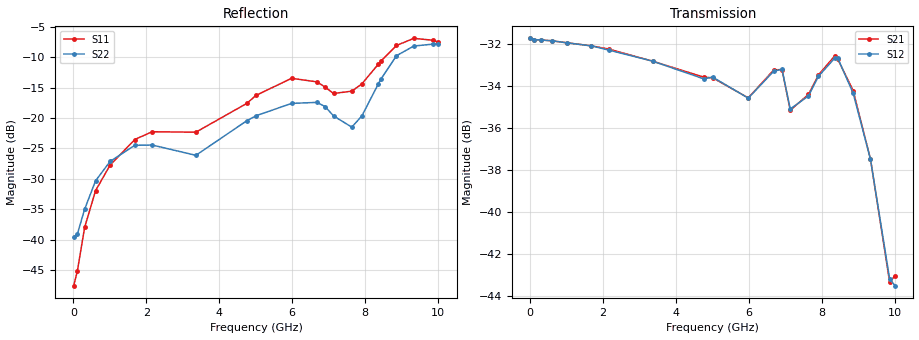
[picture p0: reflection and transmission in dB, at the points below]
! Device ID: PE43705
! Serial: 1
! Insertion: A
! Impedance: 50 ohm
! Temp: 25C
! VDD: 3.400V
! Attenuation Step: 30.75dB
#  Hz  S  RI  R  50
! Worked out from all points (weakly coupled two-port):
!   401 points, 10 MHz to 10.01 GHz, reference 50 ohm
!   highest |S21| = -31.74 dB at 10 MHz (marker M1); lowest = -43.3 dB at 9.86 GHz (marker M2)
!   lowest |S11| = -47.5 dB at 10 MHz (marker M3), VSWR 1.01, Z = 49.6 + j0.0377 ohm
!   |S11| at or under -10 dB: start of sweep to 8.524 GHz
!   |S22| runs from -39.6 to -7.8 dB; largest |S21 - S12| = 0.00078
!   S11 on the Smith chart (normalised r, x): 10 MHz: 0.99, +0.00; 4.76 GHz: 0.79, +0.12; 8.435 GHz: 0.79, +0.50; 9.335 GHz: 0.51, +0.52; 10.01 GHz: 0.46, +0.30
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1e7  -0.0042 0.00038  0.0259 -8.53e-05  0.0259 -0.000139  -0.0106 0.000558
1.1e8  -0.00389 0.00395  0.0257 -0.000706  0.0257 -0.000656  -0.00986 0.00518
3.1e8  -0.00645 0.0109  0.0256 -0.0019  0.0256 -0.00187  -0.0116 0.0136
6.1e8  -0.0161 0.0196  0.0253 -0.00357  0.0253 -0.00359  -0.0189 0.024
1.01e9  -0.0351 0.0215  0.0246 -0.00582  0.0246 -0.0058  -0.0334 0.0288
1.685e9  -0.066 0.00878  0.0231 -0.00919  0.0231 -0.00916  -0.0552 0.0227
2.16e9  -0.0769 -0.00605  0.0216 -0.0114  0.0215 -0.0113  -0.0586 0.0132
3.36e9  -0.0763 -0.00543  0.0168 -0.0155  0.0169 -0.0154  -0.0468 0.0159
4.76e9  -0.1107 0.0718  0.0121 -0.0171  0.0119 -0.017  -0.0781 0.0543
5.01e9  -0.1264 0.0868  0.0115 -0.0174  0.0115 -0.0175  -0.0865 0.0584
5.985e9  -0.1808 0.11  0.00777 -0.017  0.0077 -0.017  -0.1148 0.0646
6.685e9  -0.1727 0.0963  0.0071 -0.0206  0.00695 -0.0205  -0.1237 0.0523
6.91e9  -0.1537 0.0907  0.00379 -0.0215  0.00389 -0.0215  -0.1133 0.0493
7.135e9  -0.1393 0.0763  0.00304 -0.0172  0.00317 -0.0173  -0.0916 0.0491
7.635e9  -0.0905 0.1392  0.0041 -0.0186  0.00424 -0.0184  -0.05 0.0677
7.91e9  -0.0564 0.1818  0.00357 -0.0209  0.00382 -0.0207  -0.037 0.0971
8.36e9  -0.0324 0.2736  -0.00345 -0.0233  -0.00347 -0.023  -0.0359 0.1864
8.435e9  -0.0351 0.2907  -0.00493 -0.0226  -0.00517 -0.0227  -0.0404 0.2047
8.86e9  -0.0868 0.3836  -0.00946 -0.017  -0.00942 -0.0167  -0.1039 0.307
9.335e9  -0.1822 0.4112  -0.00875 -0.0101  -0.00873 -0.0101  -0.2093 0.328
9.86e9  -0.2921 0.3212  -0.00247 -0.00635  -0.00232 -0.00653  -0.3362 0.2227
1.001e10  -0.3156 0.275  -0.000444 -0.00703  -0.000255 -0.00667  -0.367 0.1633
